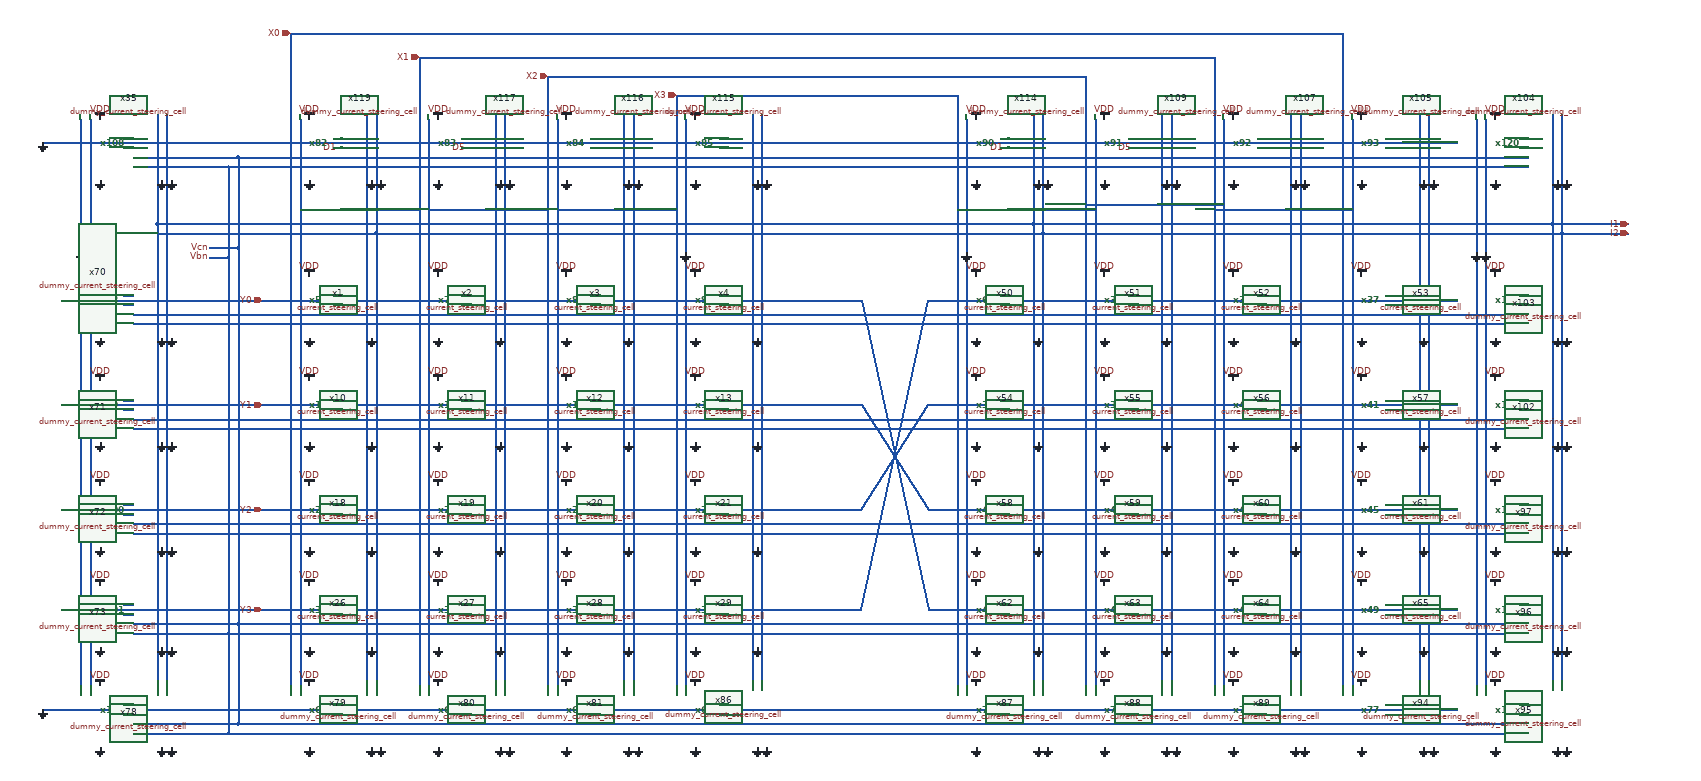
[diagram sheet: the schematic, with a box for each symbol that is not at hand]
v {xschem version=3.4.3 file_version=1.2
}
G {}
K {}
V {}
S {}
E {}
N -80 -30 -60 -30 {
lab=#net1}
N -80 -10 -60 -10 {
lab=D1}
N 190 -30 210 -30 {
lab=#net2}
N 190 -10 210 -10 {
lab=D5}
N 460 -30 480 -30 {
lab=#net3}
N 460 -10 480 -10 {
lab=#net4}
N 730 -30 750 -30 {
lab=#net5}
N 730 -10 750 -10 {
lab=#net6}
N -80 190 -60 190 {
lab=#net7}
N -80 210 -60 210 {
lab=D2}
N 190 190 210 190 {
lab=#net8}
N 190 210 210 210 {
lab=#net9}
N 460 190 480 190 {
lab=#net10}
N 460 210 480 210 {
lab=#net11}
N 730 190 750 190 {
lab=#net12}
N 730 210 750 210 {
lab=#net13}
N -80 410 -60 410 {
lab=#net14}
N -80 430 -60 430 {
lab=D3}
N 190 410 210 410 {
lab=#net15}
N 190 430 210 430 {
lab=#net16}
N 460 410 480 410 {
lab=#net17}
N 460 430 480 430 {
lab=#net18}
N 730 410 750 410 {
lab=#net19}
N 730 430 750 430 {
lab=#net20}
N -80 620 -60 620 {
lab=#net21}
N -80 640 -60 640 {
lab=D4}
N 190 620 210 620 {
lab=#net22}
N 190 640 210 640 {
lab=#net23}
N 460 620 480 620 {
lab=#net24}
N 460 640 480 640 {
lab=#net25}
N 730 620 750 620 {
lab=#net26}
N 730 640 750 640 {
lab=#net27}
N -230 -20 600 -20 {
lab=Y0}
N -230 200 600 200 {
lab=Y1}
N -230 420 600 420 {
lab=Y2}
N -230 630 600 630 {
lab=Y3}
N -170 -120 -170 580 {
lab=X0}
N 100 -120 100 580 {
lab=X1}
N 370 -120 370 580 {
lab=X2}
N 640 -120 640 580 {
lab=X3}
N -150 -120 -150 580 {
lab=X1}
N 120 -120 120 580 {
lab=X2}
N 390 -120 390 580 {
lab=X3}
N 660 -120 660 580 {
lab=GND}
N -10 -180 960 -180 {
lab=#net28}
N -10 -180 -10 570 {
lab=#net28}
N 10 -160 10 570 {
lab=#net29}
N 260 -180 260 570 {
lab=#net28}
N 530 -180 530 570 {
lab=#net28}
N 800 -180 800 570 {
lab=#net28}
N 280 -160 280 570 {
lab=#net29}
N 550 -160 550 570 {
lab=#net29}
N 820 -160 820 570 {
lab=#net29}
N 10 -160 960 -160 {
lab=#net29}
N -280 10 750 10 {
lab=Vcn}
N -280 230 750 230 {
lab=Vcn}
N -280 450 750 450 {
lab=Vcn}
N -300 -40 -300 680 {
lab=Vbn}
N -280 660 750 660 {
lab=Vcn}
N -300 680 750 680 {
lab=Vbn}
N -300 470 750 470 {
lab=Vbn}
N -300 250 750 250 {
lab=Vbn}
N -300 30 750 30 {
lab=Vbn}
N -280 -40 -280 660 {
lab=Vcn}
N -340 -110 -300 -110 {
lab=Vbn}
N -300 -110 -300 -40 {
lab=Vbn}
N -340 -130 -280 -130 {
lab=Vcn}
N -280 -130 -280 -40 {
lab=Vcn}
N 750 10 1030 10 {
lab=Vcn}
N 750 30 1030 30 {
lab=Vbn}
N 750 230 1030 230 {
lab=Vcn}
N 750 250 1030 250 {
lab=Vbn}
N 750 450 1030 450 {
lab=Vcn}
N 750 470 1030 470 {
lab=Vbn}
N 750 660 1030 660 {
lab=Vcn}
N 750 680 1030 680 {
lab=Vbn}
N 1320 -30 1340 -30 {
lab=#net1}
N 1320 -10 1340 -10 {
lab=D1}
N 1590 -30 1610 -30 {
lab=#net2}
N 1590 -10 1610 -10 {
lab=D5}
N 1860 -30 1880 -30 {
lab=#net3}
N 1860 -10 1880 -10 {
lab=#net4}
N 2130 -30 2150 -30 {
lab=#net5}
N 2130 -10 2150 -10 {
lab=#net6}
N 1320 190 1340 190 {
lab=#net7}
N 1320 210 1340 210 {
lab=D2}
N 1590 190 1610 190 {
lab=#net8}
N 1590 210 1610 210 {
lab=#net9}
N 1860 190 1880 190 {
lab=#net10}
N 1860 210 1880 210 {
lab=#net11}
N 2130 190 2150 190 {
lab=#net12}
N 2130 210 2150 210 {
lab=#net13}
N 1320 410 1340 410 {
lab=#net14}
N 1320 430 1340 430 {
lab=D3}
N 1590 410 1610 410 {
lab=#net15}
N 1590 430 1610 430 {
lab=#net16}
N 1860 410 1880 410 {
lab=#net17}
N 1860 430 1880 430 {
lab=#net18}
N 2130 410 2150 410 {
lab=#net19}
N 2130 430 2150 430 {
lab=#net20}
N 1320 620 1340 620 {
lab=#net21}
N 1320 640 1340 640 {
lab=D4}
N 1590 620 1610 620 {
lab=#net22}
N 1590 640 1610 640 {
lab=#net23}
N 1860 620 1880 620 {
lab=#net24}
N 1860 640 1880 640 {
lab=#net25}
N 2130 620 2150 620 {
lab=#net26}
N 2130 640 2150 640 {
lab=#net27}
N 1170 -20 2000 -20 {
lab=Y0}
N 1170 200 2000 200 {
lab=Y1}
N 1170 420 2000 420 {
lab=Y2}
N 1170 630 2000 630 {
lab=Y3}
N 1230 -120 1230 580 {
lab=X0}
N 1500 -120 1500 580 {
lab=X1}
N 1770 -120 1770 580 {
lab=X2}
N 2040 -120 2040 580 {
lab=X3}
N 1250 -120 1250 580 {
lab=X1}
N 1520 -120 1520 580 {
lab=X2}
N 1790 -120 1790 580 {
lab=X3}
N 2060 -120 2060 580 {
lab=GND}
N 1390 -180 2360 -180 {
lab=#net28}
N 1390 -180 1390 570 {
lab=#net28}
N 1410 -160 1410 570 {
lab=#net29}
N 1660 -180 1660 570 {
lab=#net28}
N 1930 -180 1930 570 {
lab=#net28}
N 2200 -180 2200 570 {
lab=#net28}
N 1680 -160 1680 570 {
lab=#net29}
N 1950 -160 1950 570 {
lab=#net29}
N 2220 -160 2220 570 {
lab=#net29}
N 1410 -160 2360 -160 {
lab=#net29}
N 1120 10 2150 10 {
lab=Vcn}
N 1120 230 2150 230 {
lab=Vcn}
N 1120 450 2150 450 {
lab=Vcn}
N 1120 660 2150 660 {
lab=Vcn}
N 1100 680 2150 680 {
lab=Vbn}
N 1100 470 2150 470 {
lab=Vbn}
N 1100 250 2150 250 {
lab=Vbn}
N 1100 30 2150 30 {
lab=Vbn}
N 2150 10 2430 10 {
lab=Vcn}
N 2150 30 2430 30 {
lab=Vbn}
N 2150 230 2430 230 {
lab=Vcn}
N 2150 250 2430 250 {
lab=Vbn}
N 2150 450 2430 450 {
lab=Vcn}
N 2150 470 2430 470 {
lab=Vbn}
N 2150 660 2430 660 {
lab=Vcn}
N 2150 680 2430 680 {
lab=Vbn}
N 600 -20 1030 -20 {}
N 600 200 1030 200 {}
N 600 420 1030 420 {}
N 600 630 1030 630 {}
N 1030 630 1170 -20 {}
N 1030 420 1170 200 {}
N 1030 200 1170 420 {}
N 1030 -20 1170 630 {}
N -80 830 -60 830 {
lab=#net21}
N -80 850 -60 850 {
lab=D4}
N 190 830 210 830 {
lab=#net22}
N 190 850 210 850 {
lab=#net23}
N 460 830 480 830 {
lab=#net24}
N 460 850 480 850 {
lab=#net25}
N 730 830 750 830 {
lab=#net26}
N 730 850 750 850 {
lab=#net27}
N -230 840 600 840 {
lab=Y3}
N -280 870 750 870 {
lab=Vcn}
N -300 890 750 890 {
lab=Vbn}
N 750 870 1030 870 {
lab=Vcn}
N 750 890 1030 890 {
lab=Vbn}
N 1320 830 1340 830 {
lab=#net21}
N 1320 850 1340 850 {
lab=D4}
N 1590 830 1610 830 {
lab=#net22}
N 1590 850 1610 850 {
lab=#net23}
N 1860 830 1880 830 {
lab=#net24}
N 1860 850 1880 850 {
lab=#net25}
N 2130 830 2150 830 {
lab=#net26}
N 2130 850 2150 850 {
lab=#net27}
N 1170 840 2000 840 {
lab=Y3}
N 1120 870 2150 870 {
lab=Vcn}
N 1100 890 2150 890 {
lab=Vbn}
N 600 840 1030 840 {}
N -80 -360 -60 -360 {
lab=#net1}
N -80 -340 -60 -340 {
lab=D1}
N 190 -360 210 -360 {
lab=#net2}
N 190 -340 210 -340 {
lab=D5}
N 460 -360 480 -360 {
lab=#net3}
N 460 -340 480 -340 {
lab=#net4}
N 730 -360 750 -360 {
lab=#net5}
N 730 -340 750 -340 {
lab=#net6}
N -230 -350 600 -350 {
lab=Y0}
N -280 -320 750 -320 {
lab=Vcn}
N -300 -300 750 -300 {
lab=Vbn}
N 750 -320 1030 -320 {
lab=Vcn}
N 750 -300 1030 -300 {
lab=Vbn}
N 1320 -360 1340 -360 {
lab=#net1}
N 1320 -340 1340 -340 {
lab=D1}
N 1590 -360 1610 -360 {
lab=#net2}
N 1590 -340 1610 -340 {
lab=D5}
N 1860 -360 1880 -360 {
lab=#net3}
N 1860 -340 1880 -340 {
lab=#net4}
N 2130 -360 2150 -360 {
lab=#net5}
N 2130 -340 2150 -340 {
lab=#net6}
N 1170 -350 2000 -350 {
lab=Y0}
N 1120 -320 2150 -320 {
lab=Vcn}
N 1100 -300 2150 -300 {
lab=Vbn}
N 2150 -320 2430 -320 {
lab=Vcn}
N 2150 -300 2430 -300 {
lab=Vbn}
N 600 -350 1030 -350 {}
N 960 -180 1390 -180 {}
N 960 -160 1410 -160 {}
N -170 -400 -170 -120 {}
N -150 -400 -150 -120 {}
N 100 -400 100 -120 {}
N 120 -400 120 -120 {}
N 370 -400 370 -120 {}
N 390 -400 390 -120 {}
N 640 -400 640 -120 {}
N 660 -400 660 -120 {}
N -520 -30 -500 -30 {
lab=#net5}
N -520 -10 -500 -10 {
lab=#net6}
N -520 190 -500 190 {
lab=#net12}
N -520 210 -500 210 {
lab=#net13}
N -520 410 -500 410 {
lab=#net19}
N -520 430 -500 430 {
lab=#net20}
N -520 620 -500 620 {
lab=#net26}
N -520 640 -500 640 {
lab=#net27}
N -610 -120 -610 580 {
lab=X3}
N -590 -120 -590 580 {
lab=GND}
N -450 -180 -450 570 {
lab=#net28}
N -430 -160 -430 570 {
lab=#net29}
N -520 830 -500 830 {
lab=#net26}
N -520 850 -500 850 {
lab=#net27}
N -520 -360 -500 -360 {
lab=#net5}
N -520 -340 -500 -340 {
lab=#net6}
N -610 -400 -610 -120 {}
N -590 -400 -590 -120 {}
N -300 680 -300 890 {}
N -280 660 -280 870 {}
N -500 660 -280 660 {}
N -500 680 -300 680 {}
N -500 870 -280 870 {}
N -500 890 -300 890 {}
N -500 450 -280 450 {}
N -500 470 -300 470 {}
N -500 230 -280 230 {}
N -500 250 -300 250 {}
N -500 10 -280 10 {}
N -500 30 -300 30 {}
N -500 -320 -280 -320 {}
N -500 -300 -300 -300 {}
N -300 -300 -300 -110 {}
N -280 -320 -280 -130 {}
N -650 -350 -230 -350 {}
N -690 -350 -650 -350 {}
N -590 580 -590 790 {}
N -610 580 -610 790 {}
N -650 -20 -230 -20 {}
N -650 200 -230 200 {}
N -650 420 -230 420 {}
N -650 630 -230 630 {}
N -650 840 -230 840 {}
N -450 570 -450 780 {}
N -430 570 -430 780 {}
N -150 580 -150 790 {}
N -170 580 -170 790 {}
N -10 570 -10 780 {}
N 10 570 10 780 {}
N 120 580 120 790 {}
N 100 580 100 790 {}
N 260 570 260 780 {}
N 280 570 280 780 {}
N 390 580 390 790 {}
N 370 580 370 790 {}
N 530 570 530 780 {}
N 550 570 550 780 {}
N 660 580 660 790 {}
N 640 580 640 790 {}
N 800 570 800 780 {}
N 820 570 820 780 {}
N 1230 -400 1230 -120 {}
N 1250 -400 1250 -120 {}
N 1500 -400 1500 -120 {}
N 1520 -400 1520 -120 {}
N 1770 -400 1770 -120 {}
N 1790 -400 1790 -120 {}
N 2040 -400 2040 -120 {}
N 2060 -400 2060 -120 {}
N 1250 580 1250 790 {}
N 1230 580 1230 790 {}
N 1390 570 1390 780 {}
N 1410 570 1410 780 {}
N 1520 580 1520 790 {}
N 1500 580 1500 790 {}
N 1660 570 1660 780 {}
N 1680 570 1680 780 {}
N 1790 580 1790 790 {}
N 1770 580 1770 790 {}
N 1930 570 1930 780 {}
N 1950 570 1950 780 {}
N 2060 580 2060 790 {}
N 2040 580 2040 790 {}
N 2200 570 2200 780 {}
N 2220 570 2220 780 {}
N -450 -410 -450 -180 {}
N -430 -410 -430 -160 {}
N 1390 -410 1390 -180 {}
N 1410 -410 1410 -160 {}
N -10 -410 -10 -180 {}
N 10 -410 10 -160 {}
N 260 -410 260 -180 {}
N 280 -410 280 -160 {}
N 530 -410 530 -180 {}
N 550 -410 550 -160 {}
N 800 -410 800 -180 {}
N 820 -410 820 -160 {}
N 1660 -410 1660 -180 {}
N 1680 -410 1680 -160 {}
N 1930 -410 1930 -180 {}
N 1950 -410 1950 -160 {}
N 2200 -410 2200 -180 {}
N 2220 -410 2220 -160 {}
N -450 -180 -10 -180 {}
N -450 -160 10 -160 {}
N 2410 -30 2430 -30 {
lab=#net5}
N 2410 -10 2430 -10 {
lab=#net6}
N 2410 190 2430 190 {
lab=#net12}
N 2410 210 2430 210 {
lab=#net13}
N 2410 410 2430 410 {
lab=#net19}
N 2410 430 2430 430 {
lab=#net20}
N 2410 620 2430 620 {
lab=#net26}
N 2410 640 2430 640 {
lab=#net27}
N 2320 -120 2320 580 {
lab=X3}
N 2340 -120 2340 580 {
lab=GND}
N 2480 -180 2480 570 {
lab=#net28}
N 2500 -160 2500 570 {
lab=#net29}
N 2410 830 2430 830 {
lab=#net26}
N 2410 850 2430 850 {
lab=#net27}
N 2410 -360 2430 -360 {
lab=#net5}
N 2410 -340 2430 -340 {
lab=#net6}
N 2320 -400 2320 -120 {}
N 2340 -400 2340 -120 {}
N 2340 580 2340 790 {}
N 2320 580 2320 790 {}
N 2480 570 2480 780 {}
N 2500 570 2500 780 {}
N 2480 -410 2480 -180 {}
N 2500 -410 2500 -160 {}
N 2000 -350 2280 -350 {}
N 2360 -180 2480 -180 {}
N 2360 -160 2500 -160 {}
N 2480 -180 2640 -180 {}
N 2500 -160 2640 -160 {}
N 2000 -20 2280 -20 {}
N 2000 200 2280 200 {}
N 2000 420 2280 420 {}
N 2000 630 2280 630 {}
N 2000 840 2280 840 {}
N 2150 870 2430 870 {
lab=Vcn}
N 2150 890 2430 890 {
lab=Vbn}
N 1030 -350 1170 -350 {}
N 1030 840 1170 840 {}
N 1030 890 1100 890 {}
N 1030 870 1120 870 {}
N 1030 680 1100 680 {}
N 1030 660 1120 660 {}
N 1030 470 1100 470 {}
N 1030 450 1120 450 {}
N 1030 250 1100 250 {}
N 1030 230 1120 230 {}
N 1030 30 1100 30 {}
N 1030 10 1120 10 {}
N 1030 -300 1100 -300 {}
N 1030 -320 1120 -320 {}
N 1230 -450 1230 -400 {}
N 640 -450 1230 -450 {}
N 640 -450 640 -400 {}
N 1500 -490 1500 -400 {}
N 370 -490 1500 -490 {}
N 370 -490 370 -400 {}
N 1770 -530 1770 -400 {}
N 100 -530 1770 -530 {}
N 100 -530 100 -400 {}
N 2040 -580 2040 -400 {}
N -170 -580 2040 -580 {}
N -170 -580 -170 -400 {}
N -150 -210 100 -210 {}
N 120 -210 370 -210 {}
N 390 -210 640 -210 {}
N 1230 -210 1520 -210 {}
N 1500 -220 1790 -220 {}
N 1770 -210 2060 -210 {}
N -690 840 -650 840 {}
C {madvlsi/gnd.sym} 0 60 0 0 {name=l7 lab=GND}
C {madvlsi/gnd.sym} 270 60 0 0 {name=l8 lab=GND}
C {madvlsi/gnd.sym} 540 60 0 0 {name=l9 lab=GND}
C {madvlsi/gnd.sym} 810 60 0 0 {name=l10 lab=GND}
C {madvlsi/vdd.sym} -130 -70 0 0 {name=l16 lab=VDD}
C {madvlsi/gnd.sym} -130 60 0 0 {name=l1 lab=GND}
C {madvlsi/vdd.sym} 140 -70 0 0 {name=l18 lab=VDD}
C {madvlsi/gnd.sym} 140 60 0 0 {name=l20 lab=GND}
C {madvlsi/vdd.sym} 410 -70 0 0 {name=l24 lab=VDD}
C {madvlsi/gnd.sym} 410 60 0 0 {name=l25 lab=GND}
C {madvlsi/vdd.sym} 680 -70 0 0 {name=l26 lab=VDD}
C {madvlsi/gnd.sym} 680 60 0 0 {name=l27 lab=GND}
C {madvlsi/gnd.sym} 0 280 0 0 {name=l28 lab=GND}
C {madvlsi/gnd.sym} 270 280 0 0 {name=l29 lab=GND}
C {madvlsi/gnd.sym} 540 280 0 0 {name=l30 lab=GND}
C {madvlsi/gnd.sym} 810 280 0 0 {name=l31 lab=GND}
C {madvlsi/vdd.sym} -130 150 0 0 {name=l32 lab=VDD}
C {madvlsi/gnd.sym} -130 280 0 0 {name=l33 lab=GND}
C {madvlsi/vdd.sym} 140 150 0 0 {name=l34 lab=VDD}
C {madvlsi/gnd.sym} 140 280 0 0 {name=l35 lab=GND}
C {madvlsi/vdd.sym} 410 150 0 0 {name=l36 lab=VDD}
C {madvlsi/gnd.sym} 410 280 0 0 {name=l37 lab=GND}
C {madvlsi/vdd.sym} 680 150 0 0 {name=l38 lab=VDD}
C {madvlsi/gnd.sym} 680 280 0 0 {name=l39 lab=GND}
C {madvlsi/gnd.sym} 0 500 0 0 {name=l40 lab=GND}
C {madvlsi/gnd.sym} 270 500 0 0 {name=l41 lab=GND}
C {madvlsi/gnd.sym} 540 500 0 0 {name=l42 lab=GND}
C {madvlsi/gnd.sym} 810 500 0 0 {name=l43 lab=GND}
C {madvlsi/vdd.sym} -130 370 0 0 {name=l44 lab=VDD}
C {madvlsi/gnd.sym} -130 500 0 0 {name=l45 lab=GND}
C {madvlsi/vdd.sym} 140 370 0 0 {name=l46 lab=VDD}
C {madvlsi/gnd.sym} 140 500 0 0 {name=l47 lab=GND}
C {madvlsi/vdd.sym} 410 370 0 0 {name=l48 lab=VDD}
C {madvlsi/gnd.sym} 410 500 0 0 {name=l49 lab=GND}
C {madvlsi/vdd.sym} 680 370 0 0 {name=l50 lab=VDD}
C {madvlsi/gnd.sym} 680 500 0 0 {name=l51 lab=GND}
C {madvlsi/gnd.sym} 0 710 0 0 {name=l52 lab=GND}
C {madvlsi/gnd.sym} 270 710 0 0 {name=l53 lab=GND}
C {madvlsi/gnd.sym} 540 710 0 0 {name=l54 lab=GND}
C {madvlsi/vdd.sym} -130 580 0 0 {name=l56 lab=VDD}
C {madvlsi/gnd.sym} -130 710 0 0 {name=l57 lab=GND}
C {madvlsi/vdd.sym} 140 580 0 0 {name=l58 lab=VDD}
C {madvlsi/gnd.sym} 140 710 0 0 {name=l59 lab=GND}
C {madvlsi/vdd.sym} 410 580 0 0 {name=l60 lab=VDD}
C {madvlsi/gnd.sym} 410 710 0 0 {name=l61 lab=GND}
C {madvlsi/vdd.sym} 680 580 0 0 {name=l62 lab=VDD}
C {madvlsi/gnd.sym} 680 710 0 0 {name=l63 lab=GND}
C {madvlsi/gnd.sym} 660 -120 3 0 {name=l64 lab=GND}
C {devices/lab_pin.sym} -70 -10 1 0 {name=p12 sig_type=std_logic lab=D1}
C {devices/lab_pin.sym} -70 210 1 0 {name=p13 sig_type=std_logic lab=D2}
C {devices/lab_pin.sym} -70 430 1 0 {name=p24 sig_type=std_logic lab=D3}
C {devices/lab_pin.sym} -70 640 1 0 {name=p25 sig_type=std_logic lab=D4}
C {devices/lab_pin.sym} 200 -10 1 0 {name=p26 sig_type=std_logic lab=D5}
C {/home/madvlsi/dev/git/magic-dds/xschem/unit_cell_decoder.sym} -130 -20 0 0 {name=x5}
C {/home/madvlsi/dev/git/magic-dds/xschem/unit_cell_decoder.sym} 140 -20 0 0 {name=x7}
C {/home/madvlsi/dev/git/magic-dds/xschem/unit_cell_decoder.sym} 410 -20 0 0 {name=x8}
C {/home/madvlsi/dev/git/magic-dds/xschem/unit_cell_decoder.sym} 680 -20 0 0 {name=x9}
C {/home/madvlsi/dev/git/magic-dds/xschem/unit_cell_decoder.sym} -130 200 0 0 {name=x14}
C {/home/madvlsi/dev/git/magic-dds/xschem/unit_cell_decoder.sym} 140 200 0 0 {name=x15}
C {/home/madvlsi/dev/git/magic-dds/xschem/unit_cell_decoder.sym} 410 200 0 0 {name=x16}
C {/home/madvlsi/dev/git/magic-dds/xschem/unit_cell_decoder.sym} 680 200 0 0 {name=x17}
C {/home/madvlsi/dev/git/magic-dds/xschem/unit_cell_decoder.sym} -130 420 0 0 {name=x22}
C {/home/madvlsi/dev/git/magic-dds/xschem/unit_cell_decoder.sym} 140 420 0 0 {name=x23}
C {/home/madvlsi/dev/git/magic-dds/xschem/unit_cell_decoder.sym} 410 420 0 0 {name=x24}
C {/home/madvlsi/dev/git/magic-dds/xschem/unit_cell_decoder.sym} 680 420 0 0 {name=x25}
C {/home/madvlsi/dev/git/magic-dds/xschem/unit_cell_decoder.sym} -130 630 0 0 {name=x30}
C {/home/madvlsi/dev/git/magic-dds/xschem/unit_cell_decoder.sym} 140 630 0 0 {name=x31}
C {/home/madvlsi/dev/git/magic-dds/xschem/unit_cell_decoder.sym} 410 630 0 0 {name=x32}
C {/home/madvlsi/dev/git/magic-dds/xschem/unit_cell_decoder.sym} 680 630 0 0 {name=x33}
C {/home/madvlsi/dev/git/magic-dds/xschem/current_steering_cell.sym} 0 -10 0 0 {name=x1}
C {/home/madvlsi/dev/git/magic-dds/xschem/current_steering_cell.sym} 270 -10 0 0 {name=x2}
C {/home/madvlsi/dev/git/magic-dds/xschem/current_steering_cell.sym} 540 -10 0 0 {name=x3}
C {/home/madvlsi/dev/git/magic-dds/xschem/current_steering_cell.sym} 810 -10 0 0 {name=x4}
C {/home/madvlsi/dev/git/magic-dds/xschem/current_steering_cell.sym} 0 210 0 0 {name=x10}
C {/home/madvlsi/dev/git/magic-dds/xschem/current_steering_cell.sym} 270 210 0 0 {name=x11}
C {/home/madvlsi/dev/git/magic-dds/xschem/current_steering_cell.sym} 540 210 0 0 {name=x12}
C {/home/madvlsi/dev/git/magic-dds/xschem/current_steering_cell.sym} 810 210 0 0 {name=x13}
C {/home/madvlsi/dev/git/magic-dds/xschem/current_steering_cell.sym} 0 430 0 0 {name=x18}
C {/home/madvlsi/dev/git/magic-dds/xschem/current_steering_cell.sym} 270 430 0 0 {name=x19}
C {/home/madvlsi/dev/git/magic-dds/xschem/current_steering_cell.sym} 540 430 0 0 {name=x20}
C {/home/madvlsi/dev/git/magic-dds/xschem/current_steering_cell.sym} 810 430 0 0 {name=x21}
C {/home/madvlsi/dev/git/magic-dds/xschem/current_steering_cell.sym} 0 640 0 0 {name=x26}
C {/home/madvlsi/dev/git/magic-dds/xschem/current_steering_cell.sym} 270 640 0 0 {name=x27}
C {/home/madvlsi/dev/git/magic-dds/xschem/current_steering_cell.sym} 540 640 0 0 {name=x28}
C {/home/madvlsi/dev/git/magic-dds/xschem/current_steering_cell.sym} 810 640 0 0 {name=x29}
C {devices/lab_pin.sym} -340 -130 0 0 {name=p27 sig_type=std_logic lab=Vcn}
C {devices/lab_pin.sym} -340 -110 0 0 {name=p29 sig_type=std_logic lab=Vbn}
C {madvlsi/gnd.sym} 1400 60 0 0 {name=l2 lab=GND}
C {madvlsi/gnd.sym} 1670 60 0 0 {name=l3 lab=GND}
C {madvlsi/gnd.sym} 1940 60 0 0 {name=l4 lab=GND}
C {madvlsi/gnd.sym} 2210 60 0 0 {name=l5 lab=GND}
C {madvlsi/vdd.sym} 1270 -70 0 0 {name=l6 lab=VDD}
C {madvlsi/gnd.sym} 1270 60 0 0 {name=l11 lab=GND}
C {madvlsi/vdd.sym} 1540 -70 0 0 {name=l12 lab=VDD}
C {madvlsi/gnd.sym} 1540 60 0 0 {name=l13 lab=GND}
C {madvlsi/vdd.sym} 1810 -70 0 0 {name=l14 lab=VDD}
C {madvlsi/gnd.sym} 1810 60 0 0 {name=l15 lab=GND}
C {madvlsi/vdd.sym} 2080 -70 0 0 {name=l17 lab=VDD}
C {madvlsi/gnd.sym} 2080 60 0 0 {name=l19 lab=GND}
C {madvlsi/gnd.sym} 1400 280 0 0 {name=l21 lab=GND}
C {madvlsi/gnd.sym} 1670 280 0 0 {name=l22 lab=GND}
C {madvlsi/gnd.sym} 1940 280 0 0 {name=l23 lab=GND}
C {madvlsi/gnd.sym} 2210 280 0 0 {name=l65 lab=GND}
C {madvlsi/vdd.sym} 1270 150 0 0 {name=l66 lab=VDD}
C {madvlsi/gnd.sym} 1270 280 0 0 {name=l67 lab=GND}
C {madvlsi/vdd.sym} 1540 150 0 0 {name=l68 lab=VDD}
C {madvlsi/gnd.sym} 1540 280 0 0 {name=l69 lab=GND}
C {madvlsi/vdd.sym} 1810 150 0 0 {name=l70 lab=VDD}
C {madvlsi/gnd.sym} 1810 280 0 0 {name=l73 lab=GND}
C {madvlsi/vdd.sym} 2080 150 0 0 {name=l74 lab=VDD}
C {madvlsi/gnd.sym} 2080 280 0 0 {name=l75 lab=GND}
C {madvlsi/gnd.sym} 1400 500 0 0 {name=l76 lab=GND}
C {madvlsi/gnd.sym} 1670 500 0 0 {name=l77 lab=GND}
C {madvlsi/gnd.sym} 1940 500 0 0 {name=l78 lab=GND}
C {madvlsi/gnd.sym} 2210 500 0 0 {name=l79 lab=GND}
C {madvlsi/vdd.sym} 1270 370 0 0 {name=l80 lab=VDD}
C {madvlsi/gnd.sym} 1270 500 0 0 {name=l81 lab=GND}
C {madvlsi/vdd.sym} 1540 370 0 0 {name=l82 lab=VDD}
C {madvlsi/gnd.sym} 1540 500 0 0 {name=l83 lab=GND}
C {madvlsi/vdd.sym} 1810 370 0 0 {name=l84 lab=VDD}
C {madvlsi/gnd.sym} 1810 500 0 0 {name=l85 lab=GND}
C {madvlsi/vdd.sym} 2080 370 0 0 {name=l86 lab=VDD}
C {madvlsi/gnd.sym} 2080 500 0 0 {name=l87 lab=GND}
C {madvlsi/gnd.sym} 1400 710 0 0 {name=l88 lab=GND}
C {madvlsi/gnd.sym} 1670 710 0 0 {name=l89 lab=GND}
C {madvlsi/gnd.sym} 1940 710 0 0 {name=l90 lab=GND}
C {madvlsi/gnd.sym} 2210 710 0 0 {name=l91 lab=GND}
C {madvlsi/vdd.sym} 1270 580 0 0 {name=l92 lab=VDD}
C {madvlsi/gnd.sym} 1270 710 0 0 {name=l93 lab=GND}
C {madvlsi/vdd.sym} 1540 580 0 0 {name=l94 lab=VDD}
C {madvlsi/gnd.sym} 1540 710 0 0 {name=l95 lab=GND}
C {madvlsi/vdd.sym} 1810 580 0 0 {name=l96 lab=VDD}
C {madvlsi/gnd.sym} 1810 710 0 0 {name=l97 lab=GND}
C {madvlsi/vdd.sym} 2080 580 0 0 {name=l98 lab=VDD}
C {madvlsi/gnd.sym} 2080 710 0 0 {name=l99 lab=GND}
C {devices/lab_pin.sym} 1330 -10 1 0 {name=p34 sig_type=std_logic lab=D1}
C {devices/lab_pin.sym} 1330 210 1 0 {name=p43 sig_type=std_logic lab=D2}
C {devices/lab_pin.sym} 1330 430 1 0 {name=p44 sig_type=std_logic lab=D3}
C {devices/lab_pin.sym} 1330 640 1 0 {name=p45 sig_type=std_logic lab=D4}
C {devices/lab_pin.sym} 1600 -10 1 0 {name=p46 sig_type=std_logic lab=D5}
C {/home/madvlsi/dev/git/magic-dds/xschem/unit_cell_decoder.sym} 1270 -20 0 0 {name=x6}
C {/home/madvlsi/dev/git/magic-dds/xschem/unit_cell_decoder.sym} 1540 -20 0 0 {name=x34}
C {/home/madvlsi/dev/git/magic-dds/xschem/unit_cell_decoder.sym} 1810 -20 0 0 {name=x36}
C {/home/madvlsi/dev/git/magic-dds/xschem/unit_cell_decoder.sym} 2080 -20 0 0 {name=x37}
C {/home/madvlsi/dev/git/magic-dds/xschem/unit_cell_decoder.sym} 1270 200 0 0 {name=x38}
C {/home/madvlsi/dev/git/magic-dds/xschem/unit_cell_decoder.sym} 1540 200 0 0 {name=x39}
C {/home/madvlsi/dev/git/magic-dds/xschem/unit_cell_decoder.sym} 1810 200 0 0 {name=x40}
C {/home/madvlsi/dev/git/magic-dds/xschem/unit_cell_decoder.sym} 2080 200 0 0 {name=x41}
C {/home/madvlsi/dev/git/magic-dds/xschem/unit_cell_decoder.sym} 1270 420 0 0 {name=x42}
C {/home/madvlsi/dev/git/magic-dds/xschem/unit_cell_decoder.sym} 1540 420 0 0 {name=x43}
C {/home/madvlsi/dev/git/magic-dds/xschem/unit_cell_decoder.sym} 1810 420 0 0 {name=x44}
C {/home/madvlsi/dev/git/magic-dds/xschem/unit_cell_decoder.sym} 2080 420 0 0 {name=x45}
C {/home/madvlsi/dev/git/magic-dds/xschem/unit_cell_decoder.sym} 1270 630 0 0 {name=x46}
C {/home/madvlsi/dev/git/magic-dds/xschem/unit_cell_decoder.sym} 1540 630 0 0 {name=x47}
C {/home/madvlsi/dev/git/magic-dds/xschem/unit_cell_decoder.sym} 1810 630 0 0 {name=x48}
C {/home/madvlsi/dev/git/magic-dds/xschem/unit_cell_decoder.sym} 2080 630 0 0 {name=x49}
C {/home/madvlsi/dev/git/magic-dds/xschem/current_steering_cell.sym} 1400 -10 0 0 {name=x50}
C {/home/madvlsi/dev/git/magic-dds/xschem/current_steering_cell.sym} 1670 -10 0 0 {name=x51}
C {/home/madvlsi/dev/git/magic-dds/xschem/current_steering_cell.sym} 1940 -10 0 0 {name=x52}
C {/home/madvlsi/dev/git/magic-dds/xschem/current_steering_cell.sym} 2210 -10 0 0 {name=x53}
C {/home/madvlsi/dev/git/magic-dds/xschem/current_steering_cell.sym} 1400 210 0 0 {name=x54}
C {/home/madvlsi/dev/git/magic-dds/xschem/current_steering_cell.sym} 1670 210 0 0 {name=x55}
C {/home/madvlsi/dev/git/magic-dds/xschem/current_steering_cell.sym} 1940 210 0 0 {name=x56}
C {/home/madvlsi/dev/git/magic-dds/xschem/current_steering_cell.sym} 2210 210 0 0 {name=x57}
C {/home/madvlsi/dev/git/magic-dds/xschem/current_steering_cell.sym} 1400 430 0 0 {name=x58}
C {/home/madvlsi/dev/git/magic-dds/xschem/current_steering_cell.sym} 1670 430 0 0 {name=x59}
C {/home/madvlsi/dev/git/magic-dds/xschem/current_steering_cell.sym} 1940 430 0 0 {name=x60}
C {/home/madvlsi/dev/git/magic-dds/xschem/current_steering_cell.sym} 2210 430 0 0 {name=x61}
C {/home/madvlsi/dev/git/magic-dds/xschem/current_steering_cell.sym} 1400 640 0 0 {name=x62}
C {/home/madvlsi/dev/git/magic-dds/xschem/current_steering_cell.sym} 1670 640 0 0 {name=x63}
C {/home/madvlsi/dev/git/magic-dds/xschem/current_steering_cell.sym} 1940 640 0 0 {name=x64}
C {/home/madvlsi/dev/git/magic-dds/xschem/current_steering_cell.sym} 2210 640 0 0 {name=x65}
C {madvlsi/gnd.sym} 810 710 0 0 {name=l101 lab=GND}
C {madvlsi/gnd.sym} 0 920 0 0 {name=l102 lab=GND}
C {madvlsi/gnd.sym} 270 920 0 0 {name=l103 lab=GND}
C {madvlsi/gnd.sym} 540 920 0 0 {name=l104 lab=GND}
C {madvlsi/gnd.sym} 810 920 0 0 {name=l105 lab=GND}
C {madvlsi/vdd.sym} -130 790 0 0 {name=l106 lab=VDD}
C {madvlsi/gnd.sym} -130 920 0 0 {name=l107 lab=GND}
C {madvlsi/vdd.sym} 140 790 0 0 {name=l108 lab=VDD}
C {madvlsi/gnd.sym} 140 920 0 0 {name=l109 lab=GND}
C {madvlsi/vdd.sym} 410 790 0 0 {name=l110 lab=VDD}
C {madvlsi/gnd.sym} 410 920 0 0 {name=l111 lab=GND}
C {madvlsi/vdd.sym} 680 790 0 0 {name=l112 lab=VDD}
C {madvlsi/gnd.sym} 680 920 0 0 {name=l113 lab=GND}
C {devices/lab_pin.sym} -70 850 1 0 {name=p28 sig_type=std_logic lab=D4}
C {/home/madvlsi/dev/git/magic-dds/xschem/unit_cell_decoder.sym} -130 840 0 0 {name=x66}
C {/home/madvlsi/dev/git/magic-dds/xschem/unit_cell_decoder.sym} 140 840 0 0 {name=x67}
C {/home/madvlsi/dev/git/magic-dds/xschem/unit_cell_decoder.sym} 410 840 0 0 {name=x68}
C {/home/madvlsi/dev/git/magic-dds/xschem/unit_cell_decoder.sym} 680 840 0 0 {name=x69}
C {madvlsi/gnd.sym} 1400 920 0 0 {name=l114 lab=GND}
C {madvlsi/gnd.sym} 1670 920 0 0 {name=l115 lab=GND}
C {madvlsi/gnd.sym} 1940 920 0 0 {name=l116 lab=GND}
C {madvlsi/gnd.sym} 2210 920 0 0 {name=l117 lab=GND}
C {madvlsi/vdd.sym} 1270 790 0 0 {name=l118 lab=VDD}
C {madvlsi/gnd.sym} 1270 920 0 0 {name=l119 lab=GND}
C {madvlsi/vdd.sym} 1540 790 0 0 {name=l120 lab=VDD}
C {madvlsi/gnd.sym} 1540 920 0 0 {name=l121 lab=GND}
C {madvlsi/vdd.sym} 1810 790 0 0 {name=l122 lab=VDD}
C {madvlsi/gnd.sym} 1810 920 0 0 {name=l123 lab=GND}
C {madvlsi/vdd.sym} 2080 790 0 0 {name=l124 lab=VDD}
C {madvlsi/gnd.sym} 2080 920 0 0 {name=l125 lab=GND}
C {devices/lab_pin.sym} 1330 850 1 0 {name=p30 sig_type=std_logic lab=D4}
C {/home/madvlsi/dev/git/magic-dds/xschem/unit_cell_decoder.sym} 1270 840 0 0 {name=x74}
C {/home/madvlsi/dev/git/magic-dds/xschem/unit_cell_decoder.sym} 1540 840 0 0 {name=x75}
C {/home/madvlsi/dev/git/magic-dds/xschem/unit_cell_decoder.sym} 1810 840 0 0 {name=x76}
C {/home/madvlsi/dev/git/magic-dds/xschem/unit_cell_decoder.sym} 2080 840 0 0 {name=x77}
C {madvlsi/gnd.sym} 0 -270 0 0 {name=l55 lab=GND}
C {madvlsi/gnd.sym} 270 -270 0 0 {name=l126 lab=GND}
C {madvlsi/gnd.sym} 540 -270 0 0 {name=l127 lab=GND}
C {madvlsi/gnd.sym} 810 -270 0 0 {name=l128 lab=GND}
C {madvlsi/vdd.sym} -130 -400 0 0 {name=l129 lab=VDD}
C {madvlsi/gnd.sym} -130 -270 0 0 {name=l130 lab=GND}
C {madvlsi/vdd.sym} 140 -400 0 0 {name=l131 lab=VDD}
C {madvlsi/gnd.sym} 140 -270 0 0 {name=l132 lab=GND}
C {madvlsi/vdd.sym} 410 -400 0 0 {name=l133 lab=VDD}
C {madvlsi/gnd.sym} 410 -270 0 0 {name=l134 lab=GND}
C {madvlsi/vdd.sym} 680 -400 0 0 {name=l135 lab=VDD}
C {madvlsi/gnd.sym} 680 -270 0 0 {name=l136 lab=GND}
C {devices/lab_pin.sym} -70 -340 1 0 {name=p56 sig_type=std_logic lab=D1}
C {devices/lab_pin.sym} 200 -340 1 0 {name=p57 sig_type=std_logic lab=D5}
C {/home/madvlsi/dev/git/magic-dds/xschem/unit_cell_decoder.sym} -130 -350 0 0 {name=x82}
C {/home/madvlsi/dev/git/magic-dds/xschem/unit_cell_decoder.sym} 140 -350 0 0 {name=x83}
C {/home/madvlsi/dev/git/magic-dds/xschem/unit_cell_decoder.sym} 410 -350 0 0 {name=x84}
C {/home/madvlsi/dev/git/magic-dds/xschem/unit_cell_decoder.sym} 680 -350 0 0 {name=x85}
C {madvlsi/gnd.sym} 1400 -270 0 0 {name=l138 lab=GND}
C {madvlsi/gnd.sym} 1670 -270 0 0 {name=l139 lab=GND}
C {madvlsi/gnd.sym} 1940 -270 0 0 {name=l140 lab=GND}
C {madvlsi/gnd.sym} 2210 -270 0 0 {name=l141 lab=GND}
C {madvlsi/vdd.sym} 1270 -400 0 0 {name=l142 lab=VDD}
C {madvlsi/gnd.sym} 1270 -270 0 0 {name=l143 lab=GND}
C {madvlsi/vdd.sym} 1540 -400 0 0 {name=l144 lab=VDD}
C {madvlsi/gnd.sym} 1540 -270 0 0 {name=l145 lab=GND}
C {madvlsi/vdd.sym} 1810 -400 0 0 {name=l146 lab=VDD}
C {madvlsi/gnd.sym} 1810 -270 0 0 {name=l147 lab=GND}
C {madvlsi/vdd.sym} 2080 -400 0 0 {name=l148 lab=VDD}
C {madvlsi/gnd.sym} 2080 -270 0 0 {name=l149 lab=GND}
C {devices/lab_pin.sym} 1330 -340 1 0 {name=p67 sig_type=std_logic lab=D1}
C {devices/lab_pin.sym} 1600 -340 1 0 {name=p68 sig_type=std_logic lab=D5}
C {/home/madvlsi/dev/git/magic-dds/xschem/unit_cell_decoder.sym} 1270 -350 0 0 {name=x90}
C {/home/madvlsi/dev/git/magic-dds/xschem/unit_cell_decoder.sym} 1540 -350 0 0 {name=x91}
C {/home/madvlsi/dev/git/magic-dds/xschem/unit_cell_decoder.sym} 1810 -350 0 0 {name=x92}
C {/home/madvlsi/dev/git/magic-dds/xschem/unit_cell_decoder.sym} 2080 -350 0 0 {name=x93}
C {madvlsi/gnd.sym} -440 60 0 0 {name=l150 lab=GND}
C {madvlsi/vdd.sym} -570 -70 0 0 {name=l151 lab=VDD}
C {madvlsi/gnd.sym} -570 60 0 0 {name=l152 lab=GND}
C {madvlsi/gnd.sym} -440 280 0 0 {name=l153 lab=GND}
C {madvlsi/vdd.sym} -570 150 0 0 {name=l154 lab=VDD}
C {madvlsi/gnd.sym} -570 280 0 0 {name=l155 lab=GND}
C {madvlsi/gnd.sym} -440 500 0 0 {name=l156 lab=GND}
C {madvlsi/vdd.sym} -570 370 0 0 {name=l157 lab=VDD}
C {madvlsi/gnd.sym} -570 500 0 0 {name=l158 lab=GND}
C {madvlsi/vdd.sym} -570 580 0 0 {name=l159 lab=VDD}
C {madvlsi/gnd.sym} -570 710 0 0 {name=l160 lab=GND}
C {madvlsi/gnd.sym} -590 -120 3 0 {name=l161 lab=GND}
C {/home/madvlsi/dev/git/magic-dds/xschem/unit_cell_decoder.sym} -570 -20 0 0 {name=x98}
C {/home/madvlsi/dev/git/magic-dds/xschem/unit_cell_decoder.sym} -570 200 0 0 {name=x99}
C {/home/madvlsi/dev/git/magic-dds/xschem/unit_cell_decoder.sym} -570 420 0 0 {name=x100}
C {/home/madvlsi/dev/git/magic-dds/xschem/unit_cell_decoder.sym} -570 630 0 0 {name=x101}
C {madvlsi/gnd.sym} -440 710 0 0 {name=l162 lab=GND}
C {madvlsi/gnd.sym} -440 920 0 0 {name=l163 lab=GND}
C {madvlsi/vdd.sym} -570 790 0 0 {name=l164 lab=VDD}
C {madvlsi/gnd.sym} -570 920 0 0 {name=l165 lab=GND}
C {/home/madvlsi/dev/git/magic-dds/xschem/unit_cell_decoder.sym} -570 840 0 0 {name=x106}
C {madvlsi/gnd.sym} -440 -270 0 0 {name=l166 lab=GND}
C {madvlsi/vdd.sym} -570 -400 0 0 {name=l167 lab=VDD}
C {madvlsi/gnd.sym} -570 -270 0 0 {name=l168 lab=GND}
C {/home/madvlsi/dev/git/magic-dds/xschem/unit_cell_decoder.sym} -570 -350 0 0 {name=x108}
C {madvlsi/gnd.sym} -690 -350 0 0 {name=l137 lab=GND}
C {madvlsi/gnd.sym} -610 -120 1 0 {name=l169 lab=GND}
C {madvlsi/gnd.sym} 2490 60 0 0 {name=l170 lab=GND}
C {madvlsi/vdd.sym} 2360 -70 0 0 {name=l171 lab=VDD}
C {madvlsi/gnd.sym} 2360 60 0 0 {name=l172 lab=GND}
C {madvlsi/gnd.sym} 2490 280 0 0 {name=l173 lab=GND}
C {madvlsi/vdd.sym} 2360 150 0 0 {name=l174 lab=VDD}
C {madvlsi/gnd.sym} 2360 280 0 0 {name=l175 lab=GND}
C {madvlsi/gnd.sym} 2490 500 0 0 {name=l176 lab=GND}
C {madvlsi/vdd.sym} 2360 370 0 0 {name=l177 lab=VDD}
C {madvlsi/gnd.sym} 2360 500 0 0 {name=l178 lab=GND}
C {madvlsi/vdd.sym} 2360 580 0 0 {name=l179 lab=VDD}
C {madvlsi/gnd.sym} 2360 710 0 0 {name=l180 lab=GND}
C {madvlsi/gnd.sym} 2340 -120 3 0 {name=l181 lab=GND}
C {/home/madvlsi/dev/git/magic-dds/xschem/unit_cell_decoder.sym} 2360 -20 0 0 {name=x110}
C {/home/madvlsi/dev/git/magic-dds/xschem/unit_cell_decoder.sym} 2360 200 0 0 {name=x111}
C {/home/madvlsi/dev/git/magic-dds/xschem/unit_cell_decoder.sym} 2360 420 0 0 {name=x112}
C {/home/madvlsi/dev/git/magic-dds/xschem/unit_cell_decoder.sym} 2360 630 0 0 {name=x113}
C {madvlsi/gnd.sym} 2490 710 0 0 {name=l182 lab=GND}
C {madvlsi/gnd.sym} 2490 920 0 0 {name=l183 lab=GND}
C {madvlsi/vdd.sym} 2360 790 0 0 {name=l184 lab=VDD}
C {madvlsi/gnd.sym} 2360 920 0 0 {name=l185 lab=GND}
C {/home/madvlsi/dev/git/magic-dds/xschem/unit_cell_decoder.sym} 2360 840 0 0 {name=x118}
C {madvlsi/gnd.sym} 2490 -270 0 0 {name=l186 lab=GND}
C {madvlsi/vdd.sym} 2360 -400 0 0 {name=l187 lab=VDD}
C {madvlsi/gnd.sym} 2360 -270 0 0 {name=l188 lab=GND}
C {/home/madvlsi/dev/git/magic-dds/xschem/unit_cell_decoder.sym} 2360 -350 0 0 {name=x120}
C {madvlsi/gnd.sym} 2320 -120 1 0 {name=l190 lab=GND}
C {madvlsi/gnd.sym} 1250 -120 3 0 {name=l100 lab=GND}
C {devices/ipin.sym} 2640 -180 2 0 {name=p4 lab=I1}
C {devices/ipin.sym} 2640 -160 2 0 {name=p9 lab=I2}
C {devices/ipin.sym} -170 -580 0 0 {name=p10 lab=X0}
C {devices/ipin.sym} 100 -530 0 0 {name=p14 lab=X1}
C {devices/ipin.sym} 370 -490 0 0 {name=p15 lab=X2}
C {devices/ipin.sym} 640 -450 0 0 {name=p16 lab=X3}
C {devices/ipin.sym} -230 -20 1 0 {name=p5 lab=Y0}
C {devices/ipin.sym} -230 200 1 0 {name=p6 lab=Y1}
C {devices/ipin.sym} -230 420 1 0 {name=p7 lab=Y2}
C {devices/ipin.sym} -230 630 1 0 {name=p11 lab=Y3}
C {madvlsi/gnd.sym} -690 840 0 0 {name=l189 lab=GND}
C {/home/madvlsi/dev/git/magic-dds/lvs/dummy_current_steering_cell.sym} -440 -340 0 0 {name=x35}
C {/home/madvlsi/dev/git/magic-dds/lvs/dummy_current_steering_cell.sym} -440 -10 0 0 {name=x70}
C {/home/madvlsi/dev/git/magic-dds/lvs/dummy_current_steering_cell.sym} -440 210 0 0 {name=x71}
C {/home/madvlsi/dev/git/magic-dds/lvs/dummy_current_steering_cell.sym} -440 430 0 0 {name=x72}
C {/home/madvlsi/dev/git/magic-dds/lvs/dummy_current_steering_cell.sym} -440 640 0 0 {name=x73}
C {/home/madvlsi/dev/git/magic-dds/lvs/dummy_current_steering_cell.sym} -440 850 0 0 {name=x78}
C {/home/madvlsi/dev/git/magic-dds/lvs/dummy_current_steering_cell.sym} 0 850 0 0 {name=x79}
C {/home/madvlsi/dev/git/magic-dds/lvs/dummy_current_steering_cell.sym} 270 850 0 0 {name=x80}
C {/home/madvlsi/dev/git/magic-dds/lvs/dummy_current_steering_cell.sym} 540 850 0 0 {name=x81}
C {/home/madvlsi/dev/git/magic-dds/lvs/dummy_current_steering_cell.sym} 810 850 0 0 {name=x86}
C {/home/madvlsi/dev/git/magic-dds/lvs/dummy_current_steering_cell.sym} 1400 850 0 0 {name=x87}
C {/home/madvlsi/dev/git/magic-dds/lvs/dummy_current_steering_cell.sym} 1670 850 0 0 {name=x88}
C {/home/madvlsi/dev/git/magic-dds/lvs/dummy_current_steering_cell.sym} 1940 850 0 0 {name=x89}
C {/home/madvlsi/dev/git/magic-dds/lvs/dummy_current_steering_cell.sym} 2210 850 0 0 {name=x94}
C {/home/madvlsi/dev/git/magic-dds/lvs/dummy_current_steering_cell.sym} 2490 850 0 0 {name=x95}
C {/home/madvlsi/dev/git/magic-dds/lvs/dummy_current_steering_cell.sym} 2490 640 0 0 {name=x96}
C {/home/madvlsi/dev/git/magic-dds/lvs/dummy_current_steering_cell.sym} 2490 430 0 0 {name=x97}
C {/home/madvlsi/dev/git/magic-dds/lvs/dummy_current_steering_cell.sym} 2490 210 0 0 {name=x102}
C {/home/madvlsi/dev/git/magic-dds/lvs/dummy_current_steering_cell.sym} 2490 -10 0 0 {name=x103}
C {/home/madvlsi/dev/git/magic-dds/lvs/dummy_current_steering_cell.sym} 2490 -340 0 0 {name=x104}
C {/home/madvlsi/dev/git/magic-dds/lvs/dummy_current_steering_cell.sym} 2210 -340 0 0 {name=x105}
C {/home/madvlsi/dev/git/magic-dds/lvs/dummy_current_steering_cell.sym} 1940 -340 0 0 {name=x107}
C {/home/madvlsi/dev/git/magic-dds/lvs/dummy_current_steering_cell.sym} 1670 -340 0 0 {name=x109}
C {/home/madvlsi/dev/git/magic-dds/lvs/dummy_current_steering_cell.sym} 1400 -340 0 0 {name=x114}
C {/home/madvlsi/dev/git/magic-dds/lvs/dummy_current_steering_cell.sym} 810 -340 0 0 {name=x115}
C {/home/madvlsi/dev/git/magic-dds/lvs/dummy_current_steering_cell.sym} 540 -340 0 0 {name=x116}
C {/home/madvlsi/dev/git/magic-dds/lvs/dummy_current_steering_cell.sym} 270 -340 0 0 {name=x117}
C {/home/madvlsi/dev/git/magic-dds/lvs/dummy_current_steering_cell.sym} 0 -340 0 0 {name=x119}
C {madvlsi/gnd.sym} -420 -270 0 0 {name=l71 lab=GND}
C {madvlsi/gnd.sym} 20 -270 0 0 {name=l72 lab=GND}
C {madvlsi/gnd.sym} 290 -270 0 0 {name=l191 lab=GND}
C {madvlsi/gnd.sym} 560 -270 0 0 {name=l192 lab=GND}
C {madvlsi/gnd.sym} 830 -270 0 0 {name=l193 lab=GND}
C {madvlsi/gnd.sym} 1420 -270 0 0 {name=l194 lab=GND}
C {madvlsi/gnd.sym} 1690 -270 0 0 {name=l195 lab=GND}
C {madvlsi/gnd.sym} 1960 -270 0 0 {name=l196 lab=GND}
C {madvlsi/gnd.sym} 2230 -270 0 0 {name=l197 lab=GND}
C {madvlsi/gnd.sym} 2510 -270 0 0 {name=l198 lab=GND}
C {madvlsi/gnd.sym} 2510 60 0 0 {name=l199 lab=GND}
C {madvlsi/gnd.sym} 2510 280 0 0 {name=l200 lab=GND}
C {madvlsi/gnd.sym} 2510 500 0 0 {name=l201 lab=GND}
C {madvlsi/gnd.sym} 2510 710 0 0 {name=l202 lab=GND}
C {madvlsi/gnd.sym} 2510 920 0 0 {name=l203 lab=GND}
C {madvlsi/gnd.sym} 2230 920 0 0 {name=l204 lab=GND}
C {madvlsi/gnd.sym} 1960 920 0 0 {name=l205 lab=GND}
C {madvlsi/gnd.sym} 1690 920 0 0 {name=l206 lab=GND}
C {madvlsi/gnd.sym} 1420 920 0 0 {name=l207 lab=GND}
C {madvlsi/gnd.sym} 830 920 0 0 {name=l208 lab=GND}
C {madvlsi/gnd.sym} 560 920 0 0 {name=l209 lab=GND}
C {madvlsi/gnd.sym} 290 920 0 0 {name=l210 lab=GND}
C {madvlsi/gnd.sym} 20 920 0 0 {name=l211 lab=GND}
C {madvlsi/gnd.sym} -420 920 0 0 {name=l212 lab=GND}
C {madvlsi/gnd.sym} -420 710 0 0 {name=l213 lab=GND}
C {madvlsi/gnd.sym} -420 500 0 0 {name=l214 lab=GND}
C {madvlsi/gnd.sym} -420 280 0 0 {name=l215 lab=GND}
C {madvlsi/gnd.sym} -420 60 0 0 {name=l216 lab=GND}
